VERSION 5.8 ;
BUSBITCHARS "[]" ;
DIVIDERCHAR "/" ;
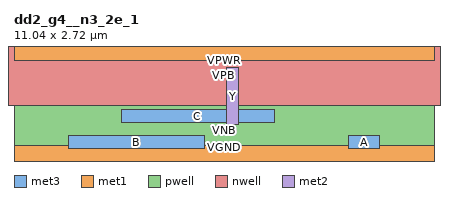
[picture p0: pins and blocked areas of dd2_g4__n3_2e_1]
MACRO dd2_g4__n3_2e_1
  CLASS CORE ;
  ORIGIN 0 0 ;
  SIZE 11.040 BY 2.720 ;
  SYMMETRY X Y ;
  SITE unithd ;
  PIN A
    DIRECTION INPUT ;
    USE SIGNAL ;
    ANTENNAGATEAREA 0.213000 ;
    PORT
      LAYER met3 ;
        RECT 8.805 0.175 9.595 0.505 ;
    END
  END A
  PIN B
    DIRECTION INPUT ;
    USE SIGNAL ;
    ANTENNAGATEAREA 0.426000 ;
    PORT
      LAYER met3 ;
        RECT 1.445 0.175 4.995 0.505 ;
    END
  END B
  PIN C
    DIRECTION INPUT ;
    USE SIGNAL ;
    ANTENNAGATEAREA 0.213000 ;
    PORT
      LAYER met3 ;
        RECT 2.825 0.855 6.835 1.185 ;
    END
  END C
  PIN VGND
    DIRECTION INOUT ;
    USE GROUND ;
    SHAPE ABUTMENT ;
    PORT
      LAYER met1 ;
        RECT 0.000 -0.240 11.040 0.240 ;
    END
  END VGND
  PIN VNB
    DIRECTION INOUT ;
    USE GROUND ;
    PORT
      LAYER pwell ;
        RECT 0.000 0.000 11.040 1.305 ;
    END
  END VNB
  PIN VPB
    DIRECTION INOUT ;
    USE POWER ;
    PORT
      LAYER nwell ;
        RECT -0.190 1.305 11.230 2.910 ;
    END
  END VPB
  PIN VPWR
    DIRECTION INOUT ;
    USE POWER ;
    SHAPE ABUTMENT ;
    PORT
      LAYER met1 ;
        RECT 0.000 2.480 11.040 2.960 ;
    END
  END VPWR
  PIN Y
    DIRECTION OUTPUT ;
    USE SIGNAL ;
    ANTENNADIFFAREA 2.399800 ;
    PORT
      LAYER met2 ;
        RECT 5.590 0.790 5.910 2.305 ;
    END
  END Y
  OBS
    LAYER li1 ;
      RECT 0.000 -0.085 11.040 0.085 ;
      RECT 1.985 0.085 2.155 0.565 ;
      RECT 7.965 0.085 8.135 0.565 ;
      RECT 0.525 0.255 0.855 0.710 ;
      RECT 5.125 0.255 5.455 0.710 ;
      RECT 9.725 0.255 10.055 0.710 ;
      RECT 1.525 0.380 1.695 1.075 ;
      RECT 1.405 1.075 1.735 1.245 ;
      RECT 2.905 0.380 3.075 1.075 ;
      RECT 2.785 1.075 3.115 1.245 ;
      RECT 4.285 0.380 4.455 1.075 ;
      RECT 4.165 1.075 4.495 1.245 ;
      RECT 6.125 0.380 6.295 1.075 ;
      RECT 6.005 1.075 6.335 1.245 ;
      RECT 7.505 0.380 7.675 1.075 ;
      RECT 7.385 1.075 7.715 1.245 ;
      RECT 8.885 0.380 9.055 1.075 ;
      RECT 8.765 1.075 9.095 1.245 ;
      RECT 1.945 1.075 2.275 1.245 ;
      RECT 1.985 1.245 2.155 2.340 ;
      RECT 3.325 1.075 3.655 1.245 ;
      RECT 3.365 1.245 3.535 2.340 ;
      RECT 4.705 1.075 5.035 1.245 ;
      RECT 4.745 1.245 4.915 2.340 ;
      RECT 6.545 1.075 6.875 1.245 ;
      RECT 6.585 1.245 6.755 2.340 ;
      RECT 7.925 1.075 8.255 1.245 ;
      RECT 7.965 1.245 8.135 2.340 ;
      RECT 9.305 1.075 9.635 1.245 ;
      RECT 9.345 1.245 9.515 2.340 ;
      RECT 0.985 1.505 1.315 2.465 ;
      RECT 3.745 1.505 4.075 2.465 ;
      RECT 5.585 1.505 5.915 2.465 ;
      RECT 6.965 1.505 7.295 2.465 ;
      RECT 10.185 1.505 10.515 2.465 ;
      RECT 2.445 1.495 2.615 2.635 ;
      RECT 8.425 1.495 8.595 2.635 ;
      RECT 0.000 2.635 11.040 2.805 ;
    LAYER met1 ;
      RECT 0.525 0.380 0.855 0.710 ;
      RECT 1.465 0.380 1.755 0.710 ;
      RECT 2.845 0.380 3.135 0.710 ;
      RECT 4.225 0.380 4.515 0.710 ;
      RECT 6.065 0.380 6.355 0.710 ;
      RECT 7.445 0.380 7.735 0.710 ;
      RECT 8.825 0.380 9.115 0.710 ;
      RECT 9.725 0.380 10.055 0.710 ;
      RECT 5.125 0.380 5.455 0.710 ;
      RECT 5.130 0.710 5.450 0.850 ;
      RECT 5.590 0.790 5.910 0.850 ;
      RECT 5.125 0.850 5.915 0.990 ;
      RECT 5.130 0.990 5.450 1.050 ;
      RECT 5.590 0.990 5.910 1.050 ;
      RECT 3.290 1.230 3.610 1.290 ;
      RECT 6.050 1.230 6.370 1.290 ;
      RECT 9.730 1.230 10.050 1.290 ;
      RECT 10.190 1.230 10.510 1.290 ;
      RECT 3.285 1.290 10.515 1.430 ;
      RECT 3.290 1.430 3.610 1.490 ;
      RECT 6.050 1.430 6.370 1.490 ;
      RECT 9.730 1.430 10.050 1.490 ;
      RECT 10.190 1.430 10.510 1.490 ;
      RECT 1.925 2.010 2.215 2.340 ;
      RECT 3.305 2.010 3.595 2.340 ;
      RECT 3.745 2.010 4.075 2.340 ;
      RECT 4.685 2.010 4.975 2.340 ;
      RECT 5.585 2.010 5.915 2.340 ;
      RECT 6.525 2.010 6.815 2.340 ;
      RECT 6.965 2.010 7.295 2.340 ;
      RECT 0.530 1.670 0.850 1.730 ;
      RECT 0.990 1.670 1.310 1.730 ;
      RECT 7.430 1.670 7.750 1.730 ;
      RECT 7.890 1.670 8.210 1.730 ;
      RECT 0.525 1.730 8.215 1.870 ;
      RECT 0.530 1.870 0.850 1.930 ;
      RECT 7.430 1.870 7.750 1.930 ;
      RECT 7.890 1.870 8.210 1.930 ;
      RECT 0.990 1.870 1.310 2.010 ;
      RECT 7.895 1.930 8.205 2.175 ;
      RECT 0.985 2.010 1.315 2.340 ;
      RECT 7.905 2.175 8.195 2.340 ;
      RECT 9.285 2.010 9.575 2.340 ;
      RECT 10.185 2.010 10.515 2.340 ;
    LAYER met2 ;
      RECT 1.470 0.155 1.750 0.210 ;
      RECT 1.450 0.210 1.770 0.675 ;
      RECT 4.230 0.155 4.510 0.210 ;
      RECT 4.210 0.210 4.530 0.675 ;
      RECT 8.830 0.155 9.110 0.210 ;
      RECT 8.810 0.210 9.130 0.675 ;
      RECT 5.130 0.415 5.450 1.050 ;
      RECT 2.830 0.415 3.150 1.150 ;
      RECT 2.850 1.150 3.130 1.205 ;
      RECT 6.050 0.415 6.370 1.490 ;
      RECT 9.730 0.415 10.050 1.490 ;
      RECT 0.530 0.415 0.850 1.930 ;
      RECT 7.430 0.415 7.750 1.930 ;
      RECT 0.990 1.670 1.310 2.305 ;
      RECT 1.930 0.155 2.210 0.210 ;
      RECT 1.910 0.210 2.230 2.305 ;
      RECT 3.290 1.230 3.610 2.305 ;
      RECT 3.770 1.515 4.050 1.570 ;
      RECT 3.750 1.570 4.070 2.305 ;
      RECT 4.690 0.155 4.970 0.210 ;
      RECT 4.670 0.210 4.990 2.305 ;
      RECT 6.530 0.835 6.810 0.890 ;
      RECT 6.510 0.890 6.830 2.305 ;
      RECT 6.990 1.515 7.270 1.570 ;
      RECT 6.970 1.570 7.290 2.305 ;
      RECT 7.890 1.670 8.210 2.305 ;
      RECT 9.290 0.155 9.570 0.210 ;
      RECT 9.270 0.210 9.590 2.305 ;
      RECT 10.190 1.230 10.510 2.305 ;
    LAYER met3 ;
      RECT 3.745 1.535 7.295 1.865 ;
  END
END dd2_g4__n3_2e_1
END LIBRARY
